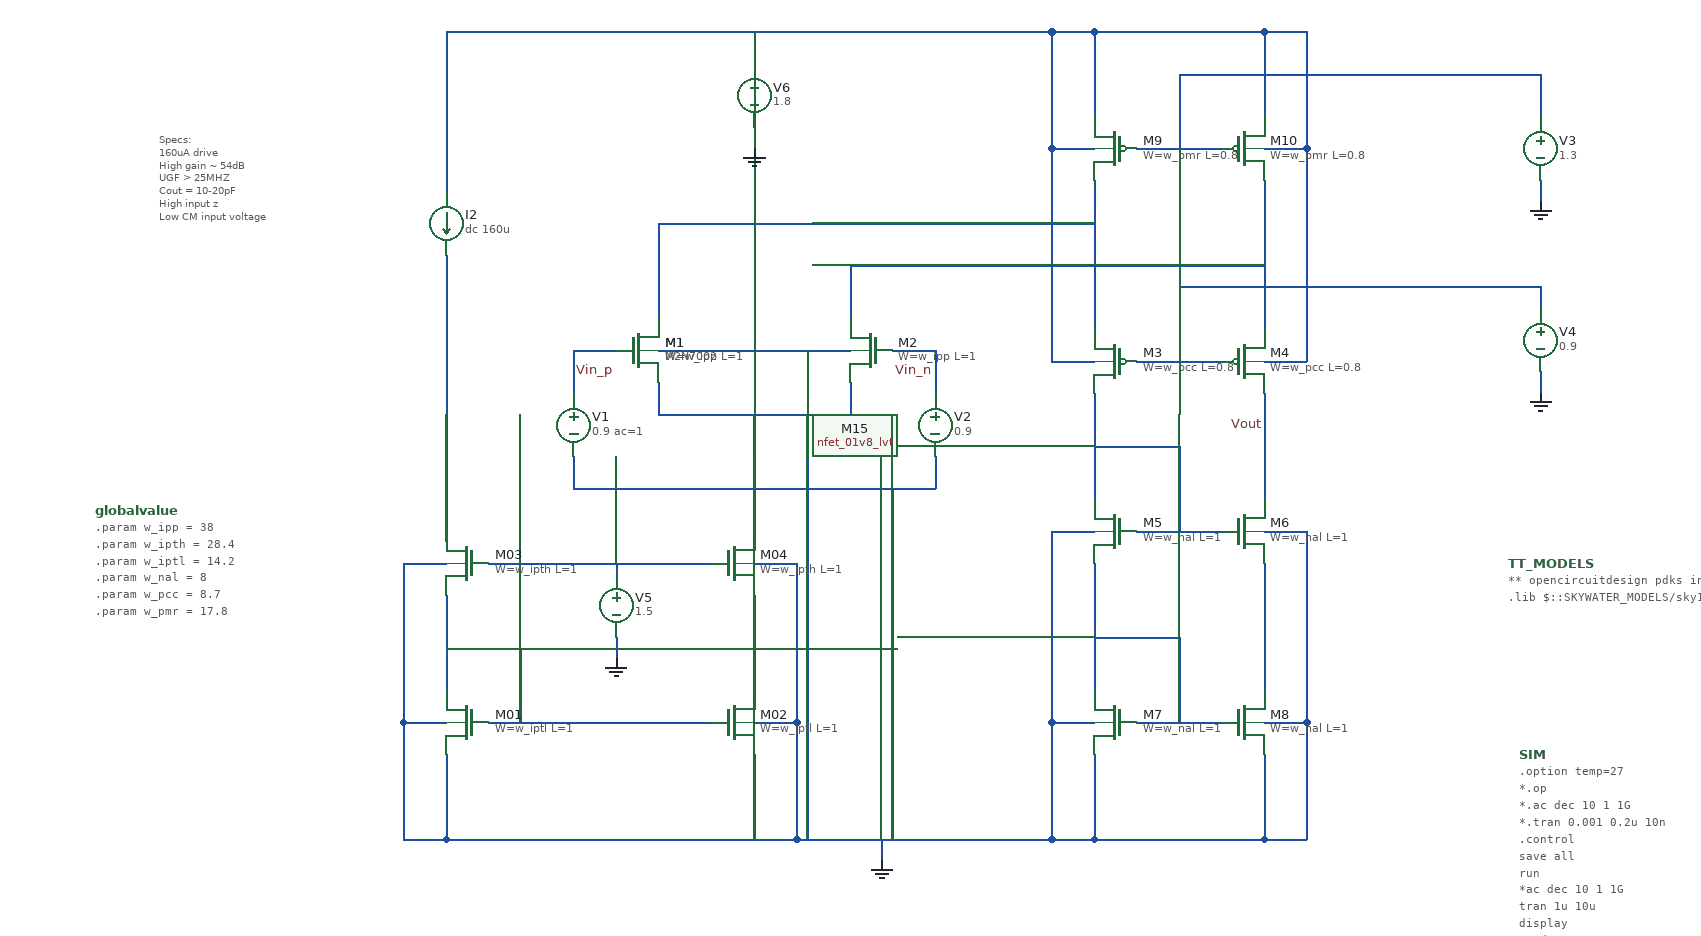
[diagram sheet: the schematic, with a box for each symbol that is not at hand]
v {xschem version=3.1.0 file_version=1.2
}
G {}
K {}
V {}
S {}
E {}
T {Specs:
160uA drive
High gain ~ 54dB
UGF > 25MHZ
Cout = 10-20pF
High input z
Low CM input voltage} 1800 -1070 0 0 0.3 0.3 {}
N 2200 -860 2230 -860 {
lab=Vin_p}
N 2190 -860 2200 -860 {
lab=Vin_p}
N 2490 -860 2500 -860 {
lab=Vin_n}
N 2270 -830 2270 -800 {
lab=#net1}
N 2300 -800 2420 -800 {
lab=#net1}
N 2450 -830 2450 -800 {
lab=#net1}
N 2720 -850 2800 -850 {
lab=#net2}
N 2720 -1050 2800 -1050 {
lab=#net3}
N 2840 -970 2840 -880 {
lab=#net4}
N 2360 -800 2360 -690 {
lab=#net1}
N 2360 -630 2360 -590 {
lab=#net5}
N 2360 -590 2360 -540 {
lab=#net5}
N 2070 -620 2070 -540 {
lab=#net6}
N 2070 -630 2070 -620 {
lab=#net6}
N 2420 -800 2450 -800 {
lab=#net1}
N 2270 -800 2300 -800 {
lab=#net1}
N 2680 -1020 2680 -880 {
lab=#net7}
N 2840 -1020 2840 -970 {
lab=#net4}
N 2680 -1160 2680 -1080 {
lab=#net8}
N 2680 -1160 2840 -1160 {
lab=#net8}
N 2840 -1160 2840 -1080 {
lab=#net8}
N 2640 -1050 2680 -1050 {
lab=#net8}
N 2640 -1160 2640 -1050 {
lab=#net8}
N 2640 -1160 2680 -1160 {
lab=#net8}
N 2840 -1050 2880 -1050 {
lab=#net8}
N 2880 -1160 2880 -1050 {
lab=#net8}
N 2840 -1160 2880 -1160 {
lab=#net8}
N 2450 -940 2450 -890 {
lab=#net4}
N 2490 -940 2840 -940 {
lab=#net4}
N 2270 -980 2270 -890 {
lab=#net7}
N 2310 -980 2680 -980 {
lab=#net7}
N 2640 -850 2680 -850 {
lab=#net8}
N 2640 -1050 2640 -850 {
lab=#net8}
N 2840 -850 2880 -850 {
lab=#net8}
N 2880 -1050 2880 -850 {
lab=#net8}
N 2680 -820 2680 -720 {
lab=#net9}
N 2840 -820 2840 -720 {
lab=Vout}
N 2840 -660 2840 -540 {
lab=#net10}
N 2680 -660 2680 -540 {
lab=#net11}
N 2680 -480 2680 -400 {
lab=GND}
N 2680 -400 2840 -400 {
lab=GND}
N 2840 -480 2840 -400 {
lab=GND}
N 2840 -510 2880 -510 {
lab=GND}
N 2840 -400 2880 -400 {
lab=GND}
N 2880 -510 2880 -400 {
lab=GND}
N 2880 -690 2880 -510 {
lab=GND}
N 2840 -690 2880 -690 {
lab=GND}
N 2640 -690 2680 -690 {
lab=GND}
N 2640 -690 2640 -510 {
lab=GND}
N 2640 -510 2680 -510 {
lab=GND}
N 2640 -510 2680 -510 {
lab=GND}
N 2640 -510 2640 -400 {
lab=GND}
N 2640 -400 2680 -400 {
lab=GND}
N 2720 -690 2800 -690 {
lab=#net9}
N 2720 -510 2800 -510 {
lab=#net11}
N 2360 -480 2360 -400 {
lab=GND}
N 2400 -400 2640 -400 {
lab=GND}
N 2070 -400 2400 -400 {
lab=GND}
N 2070 -480 2070 -400 {
lab=GND}
N 2360 -510 2400 -510 {
lab=GND}
N 2400 -510 2400 -400 {
lab=GND}
N 2360 -660 2400 -660 {
lab=GND}
N 2400 -660 2400 -510 {
lab=GND}
N 2030 -660 2070 -660 {
lab=GND}
N 2030 -660 2030 -510 {
lab=GND}
N 2030 -510 2070 -510 {
lab=GND}
N 2030 -510 2070 -510 {
lab=GND}
N 2030 -510 2030 -400 {
lab=GND}
N 2030 -400 2070 -400 {
lab=GND}
N 2080 -1160 2640 -1160 {
lab=#net8}
N 2110 -660 2320 -660 {
lab=#net12}
N 2110 -510 2320 -510 {
lab=#net6}
N 2500 -860 2530 -860 {
lab=Vin_n}
N 2270 -980 2310 -980 {
lab=#net7}
N 2450 -940 2490 -940 {
lab=#net4}
N 2070 -950 2070 -680 {
lab=#net13}
N 2760 -880 2760 -850 {
lab=#net2}
N 2760 -1080 2760 -1050 {
lab=#net3}
N 2270 -860 2450 -860 {
lab=GND}
N 2680 -590 2760 -590 {
lab=#net11}
N 2680 -770 2760 -770 {
lab=#net9}
N 2760 -770 2760 -690 {
lab=#net9}
N 2760 -590 2760 -510 {
lab=#net11}
N 2070 -1160 2070 -1010 {
lab=#net8}
N 2070 -1160 2080 -1160 {
lab=#net8}
N 2360 -1070 2360 -1050 {
lab=GND}
N 2360 -1160 2360 -1150 {
lab=#net8}
N 2360 -1150 2360 -1130 {
lab=#net8}
N 2410 -860 2410 -400 {
lab=GND}
N 2480 -400 2480 -380 {
lab=GND}
N 2190 -860 2190 -820 {
lab=Vin_p}
N 2190 -760 2190 -730 {
lab=GND}
N 2530 -860 2530 -820 {
lab=Vin_n}
N 2760 -1120 2760 -1080 {
lab=#net3}
N 2760 -1120 3100 -1120 {
lab=#net3}
N 3100 -1120 3100 -1080 {
lab=#net3}
N 3100 -1020 3100 -1000 {
lab=GND}
N 2760 -900 2760 -880 {
lab=#net2}
N 2760 -920 2760 -900 {
lab=#net2}
N 2760 -920 3100 -920 {
lab=#net2}
N 3100 -920 3100 -900 {
lab=#net2}
N 3100 -840 3100 -820 {
lab=GND}
N 2230 -660 2230 -650 {
lab=#net12}
N 2230 -590 2230 -570 {
lab=GND}
N 2190 -730 2530 -730 {
lab=GND}
N 2140 -580 2140 -510 {
lab=#net6}
N 2530 -760 2530 -730 {
lab=GND}
N 2490 -730 2490 -400 {
lab=GND}
N 2070 -580 2140 -580 {
lab=#net6}
C {sky130_fd_pr/doc/nfet_01v8_lvt.svg} 2250 -860 0 0 {name=M1 model=M2N7002 device=2N7002 footprint=SOT23 m=1}
C {sky130_fd_pr/nfet_01v8_lvt.sym} 2250 -860 0 0 {name=M1
L=1
W=w_ipp
nf=1
mult=1
ad="'int((nf+1)/2) * W/nf * 0.29'" 
pd="'2*int((nf+1)/2) * (W/nf + 0.29)'"
as="'int((nf+2)/2) * W/nf * 0.29'" 
ps="'2*int((nf+2)/2) * (W/nf + 0.29)'"
nrd="'0.29 / W'" nrs="'0.29 / W'"
sa=0 sb=0 sd=0
model=nfet_01v8_lvt
spiceprefix=X
}
C {sky130_fd_pr/doc/nfet_01v8_lvt.svg} 2400 -860 0 1 {name=M15 model=M2N7002 device=2N7002 footprint=SOT23 m=1}
C {sky130_fd_pr/nfet_01v8_lvt.sym} 2470 -860 0 1 {name=M2
L=1
W=w_ipp
nf=1
mult=1
ad="'int((nf+1)/2) * W/nf * 0.29'" 
pd="'2*int((nf+1)/2) * (W/nf + 0.29)'"
as="'int((nf+2)/2) * W/nf * 0.29'" 
ps="'2*int((nf+2)/2) * (W/nf + 0.29)'"
nrd="'0.29 / W'" nrs="'0.29 / W'"
sa=0 sb=0 sd=0
model=nfet_01v8_lvt
spiceprefix=X
}
C {sky130_fd_pr/nfet_01v8.sym} 2340 -660 0 0 {name=M04
L=1
W=w_ipth
nf=1 
mult=1
ad="'int((nf+1)/2) * W/nf * 0.29'" 
pd="'2*int((nf+1)/2) * (W/nf + 0.29)'"
as="'int((nf+2)/2) * W/nf * 0.29'" 
ps="'2*int((nf+2)/2) * (W/nf + 0.29)'"
nrd="'0.29 / W'" nrs="'0.29 / W'"
sa=0 sb=0 sd=0
model=nfet_01v8
spiceprefix=X
}
C {sky130_fd_pr/nfet_01v8.sym} 2820 -690 0 0 {name=M6
L=1
W=w_nal
nf=1 
mult=1
ad="'int((nf+1)/2) * W/nf * 0.29'" 
pd="'2*int((nf+1)/2) * (W/nf + 0.29)'"
as="'int((nf+2)/2) * W/nf * 0.29'" 
ps="'2*int((nf+2)/2) * (W/nf + 0.29)'"
nrd="'0.29 / W'" nrs="'0.29 / W'"
sa=0 sb=0 sd=0
model=nfet_01v8
spiceprefix=X
}
C {sky130_fd_pr/nfet_01v8.sym} 2340 -510 0 0 {name=M02
L=1
W=w_iptl
nf=1 
mult=1
ad="'int((nf+1)/2) * W/nf * 0.29'" 
pd="'2*int((nf+1)/2) * (W/nf + 0.29)'"
as="'int((nf+2)/2) * W/nf * 0.29'" 
ps="'2*int((nf+2)/2) * (W/nf + 0.29)'"
nrd="'0.29 / W'" nrs="'0.29 / W'"
sa=0 sb=0 sd=0
model=nfet_01v8
spiceprefix=X
}
C {sky130_fd_pr/pfet_01v8_lvt.sym} 2820 -1050 0 0 {name=M10
L=0.8
W=w_pmr
nf=1
mult=1
ad="'int((nf+1)/2) * W/nf * 0.29'" 
pd="'2*int((nf+1)/2) * (W/nf + 0.29)'"
as="'int((nf+2)/2) * W/nf * 0.29'" 
ps="'2*int((nf+2)/2) * (W/nf + 0.29)'"
nrd="'0.29 / W'" nrs="'0.29 / W'"
sa=0 sb=0 sd=0
model=pfet_01v8_lvt
spiceprefix=X
}
C {sky130_fd_pr/nfet_01v8.sym} 2090 -660 0 1 {name=M03
L=1
W=w_ipth
nf=1 
mult=1
ad="'int((nf+1)/2) * W/nf * 0.29'" 
pd="'2*int((nf+1)/2) * (W/nf + 0.29)'"
as="'int((nf+2)/2) * W/nf * 0.29'" 
ps="'2*int((nf+2)/2) * (W/nf + 0.29)'"
nrd="'0.29 / W'" nrs="'0.29 / W'"
sa=0 sb=0 sd=0
model=nfet_01v8
spiceprefix=X
}
C {sky130_fd_pr/nfet_01v8.sym} 2090 -510 0 1 {name=M01
L=1
W=w_iptl
nf=1 
mult=1
ad="'int((nf+1)/2) * W/nf * 0.29'" 
pd="'2*int((nf+1)/2) * (W/nf + 0.29)'"
as="'int((nf+2)/2) * W/nf * 0.29'" 
ps="'2*int((nf+2)/2) * (W/nf + 0.29)'"
nrd="'0.29 / W'" nrs="'0.29 / W'"
sa=0 sb=0 sd=0
model=nfet_01v8
spiceprefix=X
}
C {sky130_fd_pr/nfet_01v8.sym} 2820 -510 0 0 {name=M8
L=1
W=w_nal
nf=1 
mult=1
ad="'int((nf+1)/2) * W/nf * 0.29'" 
pd="'2*int((nf+1)/2) * (W/nf + 0.29)'"
as="'int((nf+2)/2) * W/nf * 0.29'" 
ps="'2*int((nf+2)/2) * (W/nf + 0.29)'"
nrd="'0.29 / W'" nrs="'0.29 / W'"
sa=0 sb=0 sd=0
model=nfet_01v8
spiceprefix=X
}
C {sky130_fd_pr/nfet_01v8.sym} 2700 -690 0 1 {name=M5
L=1
W=w_nal
nf=1 
mult=1
ad="'int((nf+1)/2) * W/nf * 0.29'" 
pd="'2*int((nf+1)/2) * (W/nf + 0.29)'"
as="'int((nf+2)/2) * W/nf * 0.29'" 
ps="'2*int((nf+2)/2) * (W/nf + 0.29)'"
nrd="'0.29 / W'" nrs="'0.29 / W'"
sa=0 sb=0 sd=0
model=nfet_01v8
spiceprefix=X
}
C {sky130_fd_pr/nfet_01v8.sym} 2700 -510 0 1 {name=M7
L=1
W=w_nal
nf=1 
mult=1
ad="'int((nf+1)/2) * W/nf * 0.29'" 
pd="'2*int((nf+1)/2) * (W/nf + 0.29)'"
as="'int((nf+2)/2) * W/nf * 0.29'" 
ps="'2*int((nf+2)/2) * (W/nf + 0.29)'"
nrd="'0.29 / W'" nrs="'0.29 / W'"
sa=0 sb=0 sd=0
model=nfet_01v8
spiceprefix=X
}
C {sky130_fd_pr/pfet_01v8_lvt.sym} 2820 -850 0 0 {name=M4
L=0.8
W=w_pcc
nf=1
mult=1
ad="'int((nf+1)/2) * W/nf * 0.29'" 
pd="'2*int((nf+1)/2) * (W/nf + 0.29)'"
as="'int((nf+2)/2) * W/nf * 0.29'" 
ps="'2*int((nf+2)/2) * (W/nf + 0.29)'"
nrd="'0.29 / W'" nrs="'0.29 / W'"
sa=0 sb=0 sd=0
model=pfet_01v8_lvt
spiceprefix=X
}
C {sky130_fd_pr/pfet_01v8_lvt.sym} 2700 -1050 0 1 {name=M9
L=0.8
W=w_pmr
nf=1
mult=1
ad="'int((nf+1)/2) * W/nf * 0.29'" 
pd="'2*int((nf+1)/2) * (W/nf + 0.29)'"
as="'int((nf+2)/2) * W/nf * 0.29'" 
ps="'2*int((nf+2)/2) * (W/nf + 0.29)'"
nrd="'0.29 / W'" nrs="'0.29 / W'"
sa=0 sb=0 sd=0
model=pfet_01v8_lvt
spiceprefix=X
}
C {sky130_fd_pr/pfet_01v8_lvt.sym} 2700 -850 0 1 {name=M3
L=0.8
W=w_pcc
nf=1
mult=1
ad="'int((nf+1)/2) * W/nf * 0.29'" 
pd="'2*int((nf+1)/2) * (W/nf + 0.29)'"
as="'int((nf+2)/2) * W/nf * 0.29'" 
ps="'2*int((nf+2)/2) * (W/nf + 0.29)'"
nrd="'0.29 / W'" nrs="'0.29 / W'"
sa=0 sb=0 sd=0
model=pfet_01v8_lvt
spiceprefix=X
}
C {code_shown.sym} 1740 -710 0 0 {name=globalvalue only_toplevel=false value="

.param w_ipp = 38
.param w_ipth = 28.4
.param w_iptl = 14.2
.param w_nal = 8
.param w_pcc = 8.7
.param w_pmr = 17.8

"}
C {isource.sym} 2070 -980 0 0 {
name=I2
value="dc 160u"
}
C {vsource.sym} 2360 -1100 0 0 {name=V6 value=1.8}
C {gnd.sym} 2360 -1050 0 0 {name=l5 lab=GND}
C {gnd.sym} 2480 -380 0 0 {name=l1 lab=GND}
C {vsource.sym} 2190 -790 0 0 {name=V1 value = "0.9 ac=1"
*value = "pulse 0s 1.8 1us 0 1.1us 1.8"
*value="pulse 0 1.2 0.1u 0.01u 0.01u 2u 16u"
}
C {vsource.sym} 3100 -1050 0 0 {name=V3 value=1.3}
C {vsource.sym} 3100 -870 0 0 {name=V4 value=0.9}
C {gnd.sym} 3100 -1000 0 0 {name=l4 lab=GND}
C {gnd.sym} 3100 -820 0 0 {name=l6 lab=GND}
C {lab_pin.sym} 2190 -840 0 1 {name=p5 sig_type=std_logic lab=Vin_p}
C {lab_pin.sym} 2530 -840 0 0 {name=p6 sig_type=std_logic lab=Vin_n}
C {code_shown.sym} 3080 -480 0 0 {name=SIM only_toplevel=false value="
.option temp=27

*.op
*.ac dec 10 1 1G
*.tran 0.001 0.2u 10n

.control
save all
run
*ac dec 10 1 1G
tran 1u 10u
display
ac dec 10 1 1G
*let phase = 180/PI*vp(Vout)

*plot vdb(Vout) phase
plot Vin_p Vout
.endc

.save all

"}
C {devices/code.sym} 3070 -660 0 0 {name=TT_MODELS
only_toplevel=true
format="tcleval( @value )"
value="
** opencircuitdesign pdks install
.lib $::SKYWATER_MODELS/sky130.lib.spice tt

"
spice_ignore=false}
C {vsource.sym} 2230 -620 0 0 {name=V5 value=1.5
}
C {gnd.sym} 2230 -570 0 0 {name=l7 lab=GND}
C {vsource.sym} 2530 -790 0 0 {name=V2 value = 0.9
*value = "pulse 0s 1.8 1us 0 1.1us 1.8"
*value="pulse 0 1.2 0.1u 0.01u 0.01u 2u 16u"
}
C {lab_pin.sym} 2840 -790 0 0 {name=p2 sig_type=std_logic lab=Vout}
